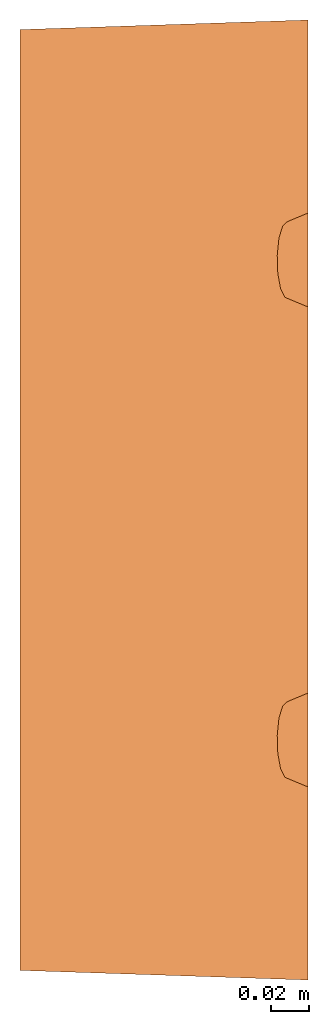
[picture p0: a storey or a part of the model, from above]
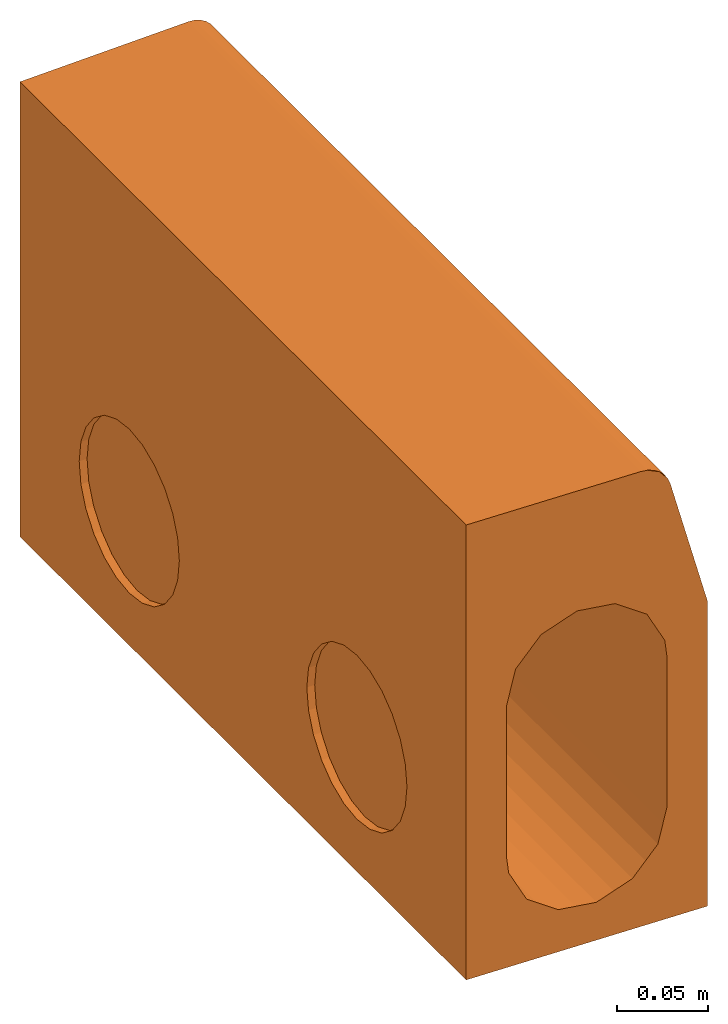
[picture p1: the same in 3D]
Properties of the parts of a building model (IFC2X3)

# File
Description: ViewDefinition [CoordinationView]
File name: 7969 - 10-8m external mitre.ifc
Time: 2013-09-12T12:56:12
Written by: Autodesk Revit 2013
Made in: 20120221_2030(x64)

# IfcProject, Project Number
LongName: Project Name; Phase: Project Status

# IfcSite, Default
RefLatitude: 42, 21, 30, 344238; RefLongitude: -71, -3, -35, -194702; RefElevation: 0 mm

# IfcBuilding
Pset_BuildingCommon - NumberOfStoreys: 2
Other - Project Name: Project Name; Project Issue Date: Issue Date; Project Address: Enter address here; Project Number: Project Number; Client Name: Owner; Project Status: Project Status

# IfcBuildingStorey (2)
Constraints - Elevation Base: 0
Graphics - Symbol at End 1 Default: no; Line Weight: 1; Color: 0; Symbol: M_Level Head - Circle: M_Level Head - Circle; Line Pattern: Center; Symbol at End 2 Default: yes
Identity Data - Structural: no; Building Story: yes
Dimensions - Computation Height: 0 mm
Name | LongName = Name | Elevation (mm) = Constraints, Elevation (mm)
T.O. Fnd. Wall | T.O. Fnd. Wall | -300
Level 1 | Level 1 | 0

# IfcBuildingElementProxy: 7969 - 10-8m external mitre, Civil-Drainage-Channel-ACO-KerbDrain-HB305 Part 2:7969 - 10-8m external mitre:7969 - 10-8m external mitre:263456
In: T.O. Fnd. Wall
Material: ACO Polymer Concrete.
Green Building Properties - Access Cover/Frame Recyclable: N/A; End Cap Recycled Material Content: N/A; Channel Recyclable: Fully recyclable; End Cap Recyclable: N/A; Access Cover/Frame Recycled Material Content: N/A; Channel Recycled Material Content: 20% minimum
Construction - KDHB305 internal_angle: no; flush drainable centre stone: no; LH drop kerb- 6m ext rad: no; KDHB305 6m _external_radius: no; KDHB305 1.8m_radius: no; KDHB305 7-6m external_mitre: no; KDHB305_quadrant: no; KDHB305 10-8m_external_mitre: yes; KDHB305 25-11m external_mitre: no; KDHB305 25-11m internal_mitre: no; KDHB305 RH drop kerb-4999: no
Phasing - Phase Created: Phase 1
Constraints - Level: Level: Level 1; Moves With Nearby Elements: no
Dimensions - Volume: 12680075 mm3; Quadrant void Start: 2600.7 mm; 1.8m Radius unit Void Start: -4800 mm; Mitre Void Start: 0 mm; Quadrant void End: 2620 mm; Flush Drainable Centre Stone Void End: -4505 mm; 1.8m Radius Unit void End: -4805 mm; Void L End: -3010 mm; mitre small length: 487 mm; Curved LH Void End: 3010 mm; Mitre Void End: -180 mm; 6m Radius unit void Start: -6000 mm; Void_Width: 150 mm; Curved RH Void Start: -3060 mm; Curved RH Void End: -3070 mm; Curved LH Void Start: 3000 mm; 6m Radius Unit Void end: -6005 mm; Void L Start: -3000 mm; Staright Void Depth: -7005 mm; Straight Void Depth: -7000 mm; Mite Long Side Length: 497 mm; Flush Drainable Centre Stone Void Start: -4500 mm; Void_Length: 500 mm
Pset_BuildingElementProxyCommon - Reference: 7969 - 10-8m external mitre
Materials and Finishes - Access Cover/Frame Material: N/A; Access Cover/Frame Colour: N/A; Connection Pipe Material Colour: N/A; End Cap Material: N/A; Channel Colour: Grey; Connection Pipe Material: N/A; Access Cover/Frame Finish: N/A; Channel Material: Vienite® Synthetic Resin Concrete; End Cap Colour: N/A
General - TagNumber: 0.000000; SerialNumber: 0.000000
Data - Product Weight: 26.7 Kg; Hydraulic Performance: http://www.aco.co.uk/download.php?id=120; Installation - Concrete Grade: Refer to brochure; Concrete Surround Volume - Load Class A 15 - D 400 - Grass or Asphalt Pavement: N/A; Load Class: A 15 - D 400; Product Dimensions: 500/490mm x 150mm x 305mm (LxWxH); Invert Depth: 280mm; Concrete Surround Volume - Load Class A 15 - D 400 - Concrete Pavement: N/A; ACO Hydraulic Design Software: http://www.acodesign.co.uk; Connection Pipe O.D: N/A; Channel C.S.A: 0.02m²; Drainage Slot Width: 50mm; Product Standard: BS EN 1433:2002, CE marked, Kitemarked; Drainage Slot Intake area: 14592mm²/m
Identity Data - Telephone: +44 (0)1462 816666; Model Description: Combined kerb and drainage system; Maintenance guidelines: http://www.aco.co.uk/download.php?id=120; Type Comments: ACO KerbDrain HB305 half battered 10-8m external mitre unit 500/490mm long; e-mail Sales: customersupport@aco.co.uk; Product Page URL: http://www.aco.co.uk/product_detail.php?id=3; Address: ACO Business Park, Hitchin Road, Shefford, Bedfordshire, United Kingdom SG17 5TE; Installation guidelines: http://www.aco.co.uk/download.php?id=120; URL: www.aco.co.uk; Product brochure: http://www.aco.co.uk/download.php?id=120; Cost: 0; Product Code: 7969; OmniClass Title: Rainwater Removal; Fax: +44 (0)1462 815895; Price: POA - contact ACO; Manufacturer: ACO Technologies plc - ACO Water Management Division; OmniClass Number: 23.70.50.24; Assembly Code: D2040; Model: ACO KerbDrain HB305; Assembly Description: Rain Water Drainage; e-mail Technical: technical@aco.co.uk
Other - Revision: 1; CreatedBy: www.aco.co.uk

# IfcOpeningElement: Recess (8)
In: Level 1
Structural - Enable Analytical Model: no; Structural: no
Constraints - Height Offset From Level: 0 mm; Level: Level: Level 1; Related to Mass: no; Room Bounding: yes
Dimensions - Area: 27858925 mm2; Thickness: 400 mm; Volume: 11130286135 mm3; Perimeter: 21157.2 mm
Phasing - Phase Created: Phase 1
Analytical Properties - Absorptance: 0.1; Roughness: 1
Construction - Function: 0; Default Thickness: 400 mm
Graphics - Coarse Scale Fill Color: 0

# IfcSlab: Floor:Generic Floor - 400mm, Floor:Generic Floor - 400mm:184025
In: Level 1
PredefinedType: FLOOR; Material: Default Floor 400 mm
Structural - Enable Analytical Model: no; Structural: no
Constraints - Height Offset From Level: 0 mm; Level: Level: Level 1; Related to Mass: no; Room Bounding: yes
Dimensions - Area: 27858925 mm2; Thickness: 400 mm; Volume: 11130286135 mm3; Perimeter: 21157.2 mm
Phasing - Phase Created: Phase 1
Pset_SlabCommon - Reference: Generic Floor - 400mm; IsExternal: no; LoadBearing: yes
Analytical Properties - Absorptance: 0.1; Roughness: 1
Construction - Function: 0; Default Thickness: 400 mm
Graphics - Coarse Scale Fill Color: 0
